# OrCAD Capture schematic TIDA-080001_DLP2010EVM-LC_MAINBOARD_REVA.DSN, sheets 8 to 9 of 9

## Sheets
8 P07: Power Supplies: size D
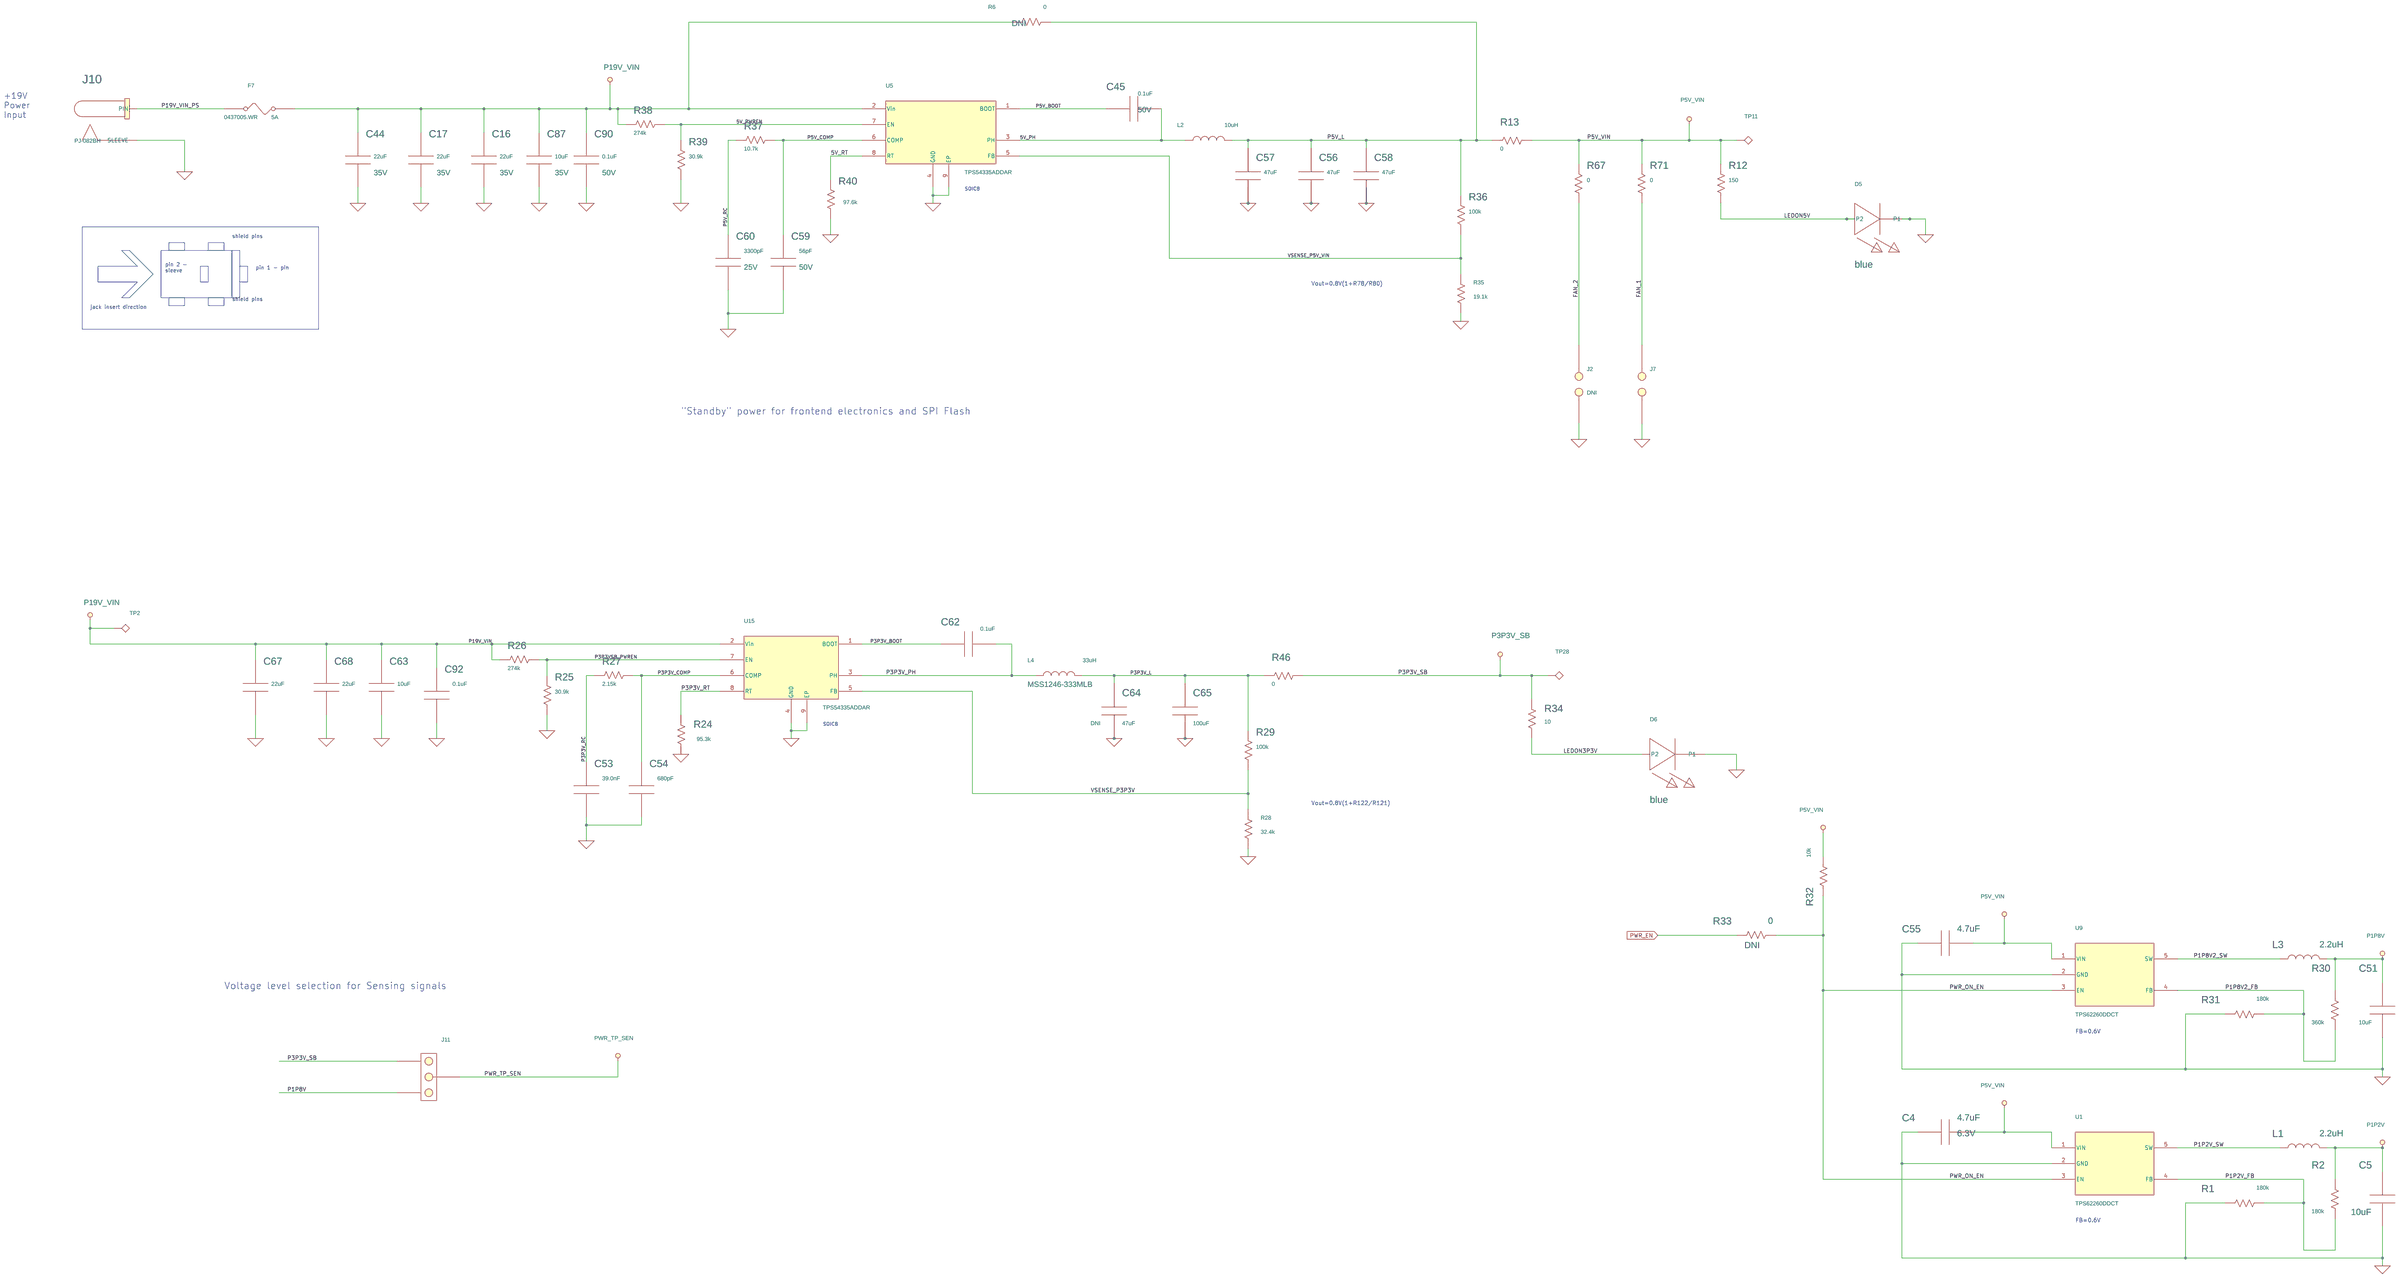
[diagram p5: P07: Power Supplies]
9 P04: MSP430, Switches, Video CN: size D

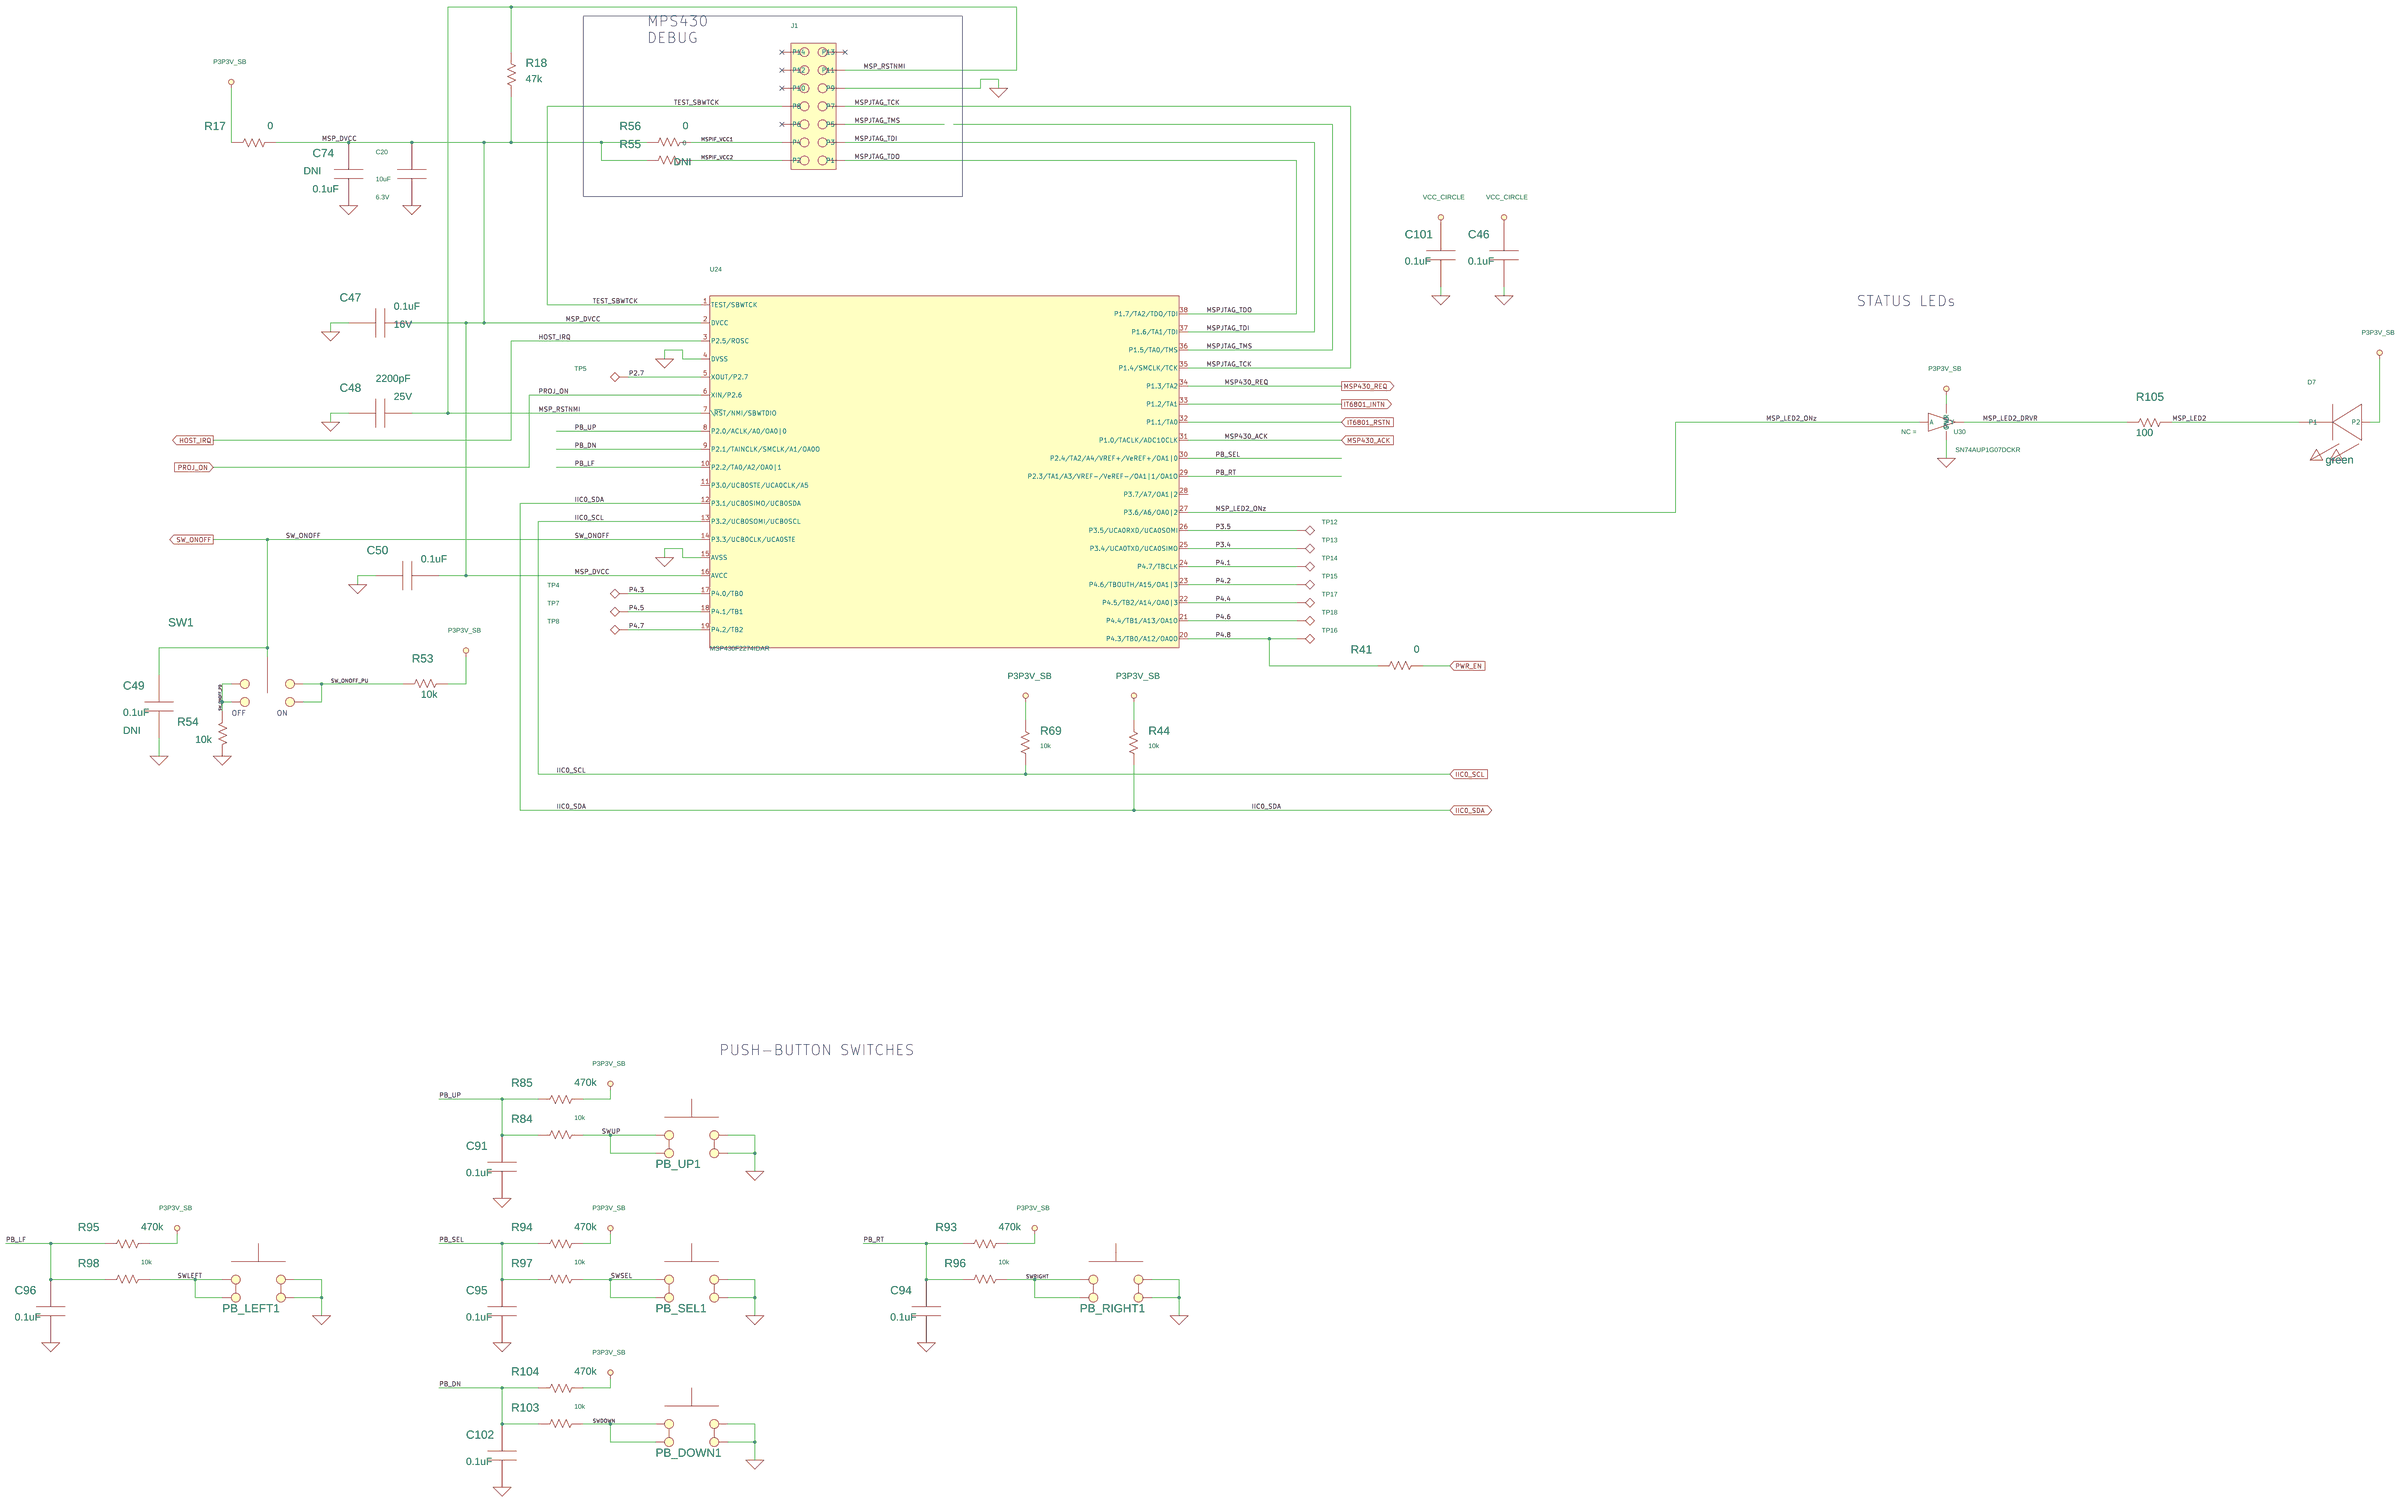
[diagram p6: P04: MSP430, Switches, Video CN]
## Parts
sheet P04: MSP430, Switches, Video CN
C20  10uF  [0603]
C46  0.1uF  [0402_AVXA]
C47  0.1uF  [0402_AVXA]
C48  2200pF  [0402]
C49  0.1uF  [0402_AVXA]
C50  0.1uF  [0402_AVXA]
C74  0.1uF  [0402_AVXA]
C91  0.1uF  [0402_AVXA]
C94  0.1uF  [0402_AVXA]
C95  0.1uF  [0402_AVXA]
C96  0.1uF  [0402_AVXA]
C101  0.1uF  [0402_AVXA]
C102  0.1uF  [0402_AVXA]
D7  green  [1206]
J1  HDR,14P,2R  [HDR14P_2R_100mil]
PB_DOWN1  KT11B1SM  [KT11B1SM]
PB_LEFT1  KT11B1SM  [KT11B1SM]
PB_RIGHT1  KT11B1SM  [KT11B1SM]
PB_SEL1  KT11B1SM  [KT11B1SM]
PB_UP1  KT11B1SM  [KT11B1SM]
R17  0  [0402]
R18  47k  [0402]
R41  0  [0402]
R44  10k  [0402]
R53  10k  [0402]
R54  10k  [0402]
R55  0  [0402]
R56  0  [0402]
R69  10k  [0402]
R84  10k  [0402]
R85  470k  [0402]
R93  470k  [0402]
R94  470k  [0402]
R95  470k  [0402]
R96  10k  [0402]
R97  10k  [0402]
R98  10k  [0402]
R103  10k  [0402]
R104  470k  [0402]
R105  100  [0402]
SW1  GT11MSCBE  [GT11MSCBE]
TP4  TP,40mil Drill,60mil Pad  [HOLE_PLATED_40mil_DRILL_60mil_PAD]
TP5  TP,40mil Drill,60mil Pad  [HOLE_PLATED_40mil_DRILL_60mil_PAD]
TP7  TP,40mil Drill,60mil Pad  [HOLE_PLATED_40mil_DRILL_60mil_PAD]
TP8  TP,40mil Drill,60mil Pad  [HOLE_PLATED_40mil_DRILL_60mil_PAD]
TP12  TP,40mil Drill,60mil Pad  [HOLE_PLATED_40mil_DRILL_60mil_PAD]
TP13  TP,40mil Drill,60mil Pad  [HOLE_PLATED_40mil_DRILL_60mil_PAD]
TP14  TP,40mil Drill,60mil Pad  [HOLE_PLATED_40mil_DRILL_60mil_PAD]
TP15  TP,40mil Drill,60mil Pad  [HOLE_PLATED_40mil_DRILL_60mil_PAD]
TP16  TP,40mil Drill,60mil Pad  [HOLE_PLATED_40mil_DRILL_60mil_PAD]
TP17  TP,40mil Drill,60mil Pad  [HOLE_PLATED_40mil_DRILL_60mil_PAD]
TP18  TP,40mil Drill,60mil Pad  [HOLE_PLATED_40mil_DRILL_60mil_PAD]
U24  MSP430F2274IDAR  [TSSOP_38_DA_R-PDSO-G]
U30  SN74AUP1G07DCK  [U_5_DCK]
sheet P07: Power Supplies
C4  4.7uF  [0402]
C5  10uF  [0603]
C16  22uF  [1206]
C17  22uF  [1206]
C44  22uF  [1206]
C45  0.1uF  [0402]
C51  10uF  [0603]
C53  39.0nF  [0402]
C54  680pF  [0402]
C55  4.7uF  [0402]
C56  47uF  [1206]
C57  47uF  [1206]
C58  47uF  [1206]
C59  56pF  [0805]
C60  3300pF  [0805]
C62  0.1uF  [0402]
C63  10uF  [0805]
C64  47uF  [1206]
C65  100uF  [1206]
C67  22uF  [1206]
C68  22uF  [1206]
C87  10uF  [0805]
C90  0.1uF  [0402]
C92  0.1uF  [0402]
D5  blue  [1206]
D6  blue  [1206]
F7  5A  [1206]
J2  HDR,2P,1R  [22Series_2P]
J7  HDR,2P,1R  [22Series_2P]
J10  PJ-082BH  [jack2_pj-082bh_cui]
J11  EM,HDR,3P,1R,2x  [HDR3X1]
L1  2.2uH  [1008_2p5mmx2mm]
L2  10uH  [IND2_XAL8080_COILCRAFT]
L3  2.2uH  [1008_2p5mmx2mm]
L4  33uH  [IND2-MSS1246_COIL]
R1  180k  [0402]
R2  180k  [0402]
R6  0  [1206]
R12  150  [0402]
R13  0  [0402]
R24  95.3k  [0402]
R25  30.9k  [0402]
R26  274k  [0402]
R27  2.15k  [0402]
R28  32.4k  [0402]
R29  100k  [0402]
R30  360k  [0402]
R31  180k  [0402]
R32  10k  [0402]
R33  0  [0402]
R34  10  [0402]
R35  19.1k  [0805]
R36  100k  [0402]
R37  10.7k  [0402]
R38  274k  [0402]
R39  30.9k  [0402]
R40  97.6k  [0402]
R46  0  [0402]
R67  0  [0402]
R71  0  [0402]
TP2  TP,12mil Drill,32mil Pad  [tp-30rd12]
TP11  TP,12mil Drill,32mil Pad  [tp-30rd12]
TP28  TP,12mil Drill,32mil Pad  [tp-30rd12]
U1  TPS62260DDCT  [TSOT-23_DDC_R-PDSO-G5]
U5  TPS54335ADDAR  [8-SO-PWRPAD_DDA_R-PDSO-G8]
U9  TPS62260DDCT  [TSOT-23_DDC_R-PDSO-G5]
U15  TPS54335ADDAR  [HSOIC8_DDA_R-PDSO-G8]

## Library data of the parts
C20 = PAS,CAP,NP,large: DigiKey: 445-4112-1-ND; DigiReel: 445-4112-6-ND; Family: passive; Index PN: 906; Lead Style: SMT; MFG: TDK; Material: x5r; P/D_NUM: C1608X5R0J106M080AB; Part Number: C1608X5R0J106M080AB; Part Specific: CAP CERAMIC 10UF 6.3V X5R 0603; Tolerance: 20%; Type: capacitor; VENDOR: TDK; VPC: 6.3V
C46 C47 C50 C91 C94-C96 C101 C102 = PAS,CAP,NP,large: DigiKey: 445-4952-1-ND; DigiReel: 445-4952-6-ND; Family: passive; Index PN: 681; Lead Style: SMT; MFG: TDK; Material: x7r; P/D_NUM: C1005X7R1C104K050BC; Part Number: C1005X7R1C104K050BC; Part Specific: CAP CER .1UF 16V X7R 0402; TOLERANCE: 10%; Type: capacitor; VENDOR: TDK; VPC: 16V
C48 = PAS,CAP,NP,large: DigiKey: 490-5419-1-ND; DigiReel: 490-5419-6-ND; Family: passive; Index PN: 1047; Lead Style: SMT; MFG: Murata; P/D_NUM: GRM155R71E222KA01D; Part Number: GRM155R71E222KA01D; Part Specific: CAP CER 2200PF 25V X7R 0402; TOLERANCE: 10%; Type: capacitor; VENDOR: Murata; VPC: 25V
C49 C74 = PAS,CAP,NP,large: DigiKey: 445-4952-1-ND; DigiReel: 445-4952-6-ND; Family: passive; Index PN: 681; Install: DNI; Lead Style: SMT; MFG: TDK; Material: x7r; P/D_NUM: C1005X7R1C104K050BC; Part Number: C1005X7R1C104K050BC; Part Specific: CAP CER .1UF 16V X7R 0402; TOLERANCE: 10%; Type: capacitor; VENDOR: TDK; VPC: 16V
D7 = PAS,DIODE,LED,large: DigiKey: 67-1357-1-ND; DigiReel: 67-1357-6-ND; Family: passive; Index PN: 31; Install: Y; Lead Style: SMT; MFG: Lumex; P/D_NUM: SML-LX1206GC-TR; Part Number: SML-LX1206GC-TR; Part Specific: LED 565NM WTR CLR GREEN 1206 SMD; Type: diode,led; VENDOR: Lumex
J1 = EM,HDR,14P,2R,2X,Narrow: DigiKey: SAM1052-07-ND; DigiReel: ---; Family: electro/mechanical; Index PN: 18; Install: Y; Lead Style: TH; MFG: Samtec; P/D_NUM: TSW-107-14-G-D; Part Number: TSW-107-14-G-D; Part Specific: CONN HEADER 14POS .100in DL GOLD; Pin Cnt: 14; Pin Spacing: 100x100mil; Row Cnt: 2; Type: header; VENDOR: Samtec
PB_DOWN1 PB_LEFT1 PB_RIGHT1 PB_SEL1 PB_UP1 = EM,SW,KT11BxSM34LFx: DigiKey: CKN1838CT-ND; DigiReel: CKN1838DKR-ND; Family: electro/mechanical; Index PN: 991; Lead Style: SMT; MFG: C&K; Part Number: KT11B1SM34LFS; Part Specific: SWITCH TACT 0.64MM SILV GWING; Type: switch
R17 R41 = PAS,R,large: DigiKey: P0.0JCT-ND; DigiReel: P0.0JDKR-ND; Family: passive; Index PN: 687; Lead Style: SMT; MFG: Panasonic; Material: chip; P/D_NUM: ERJ-2GE0R00X; Part Number: ERJ-2GE0R00X; Part Specific: RES 0.0 OHM 1/16W 0402 SMD; Power: 1/16W; Type: resistor; VPC: 1/16W; Vendor: Panasonic
R18 = PAS,R,large: DigiKey: P47.0KLCT-ND; DigiReel: P47.0KLDKR-ND; Family: passive; Index PN: 1030; Lead Style: SMT; MFG: Panasonic; Material: chip; P/D_NUM: ERJ-2RKF4702X; Part Number: ERJ-2RKF4702X; Part Specific: RES 47.0K OHM 1/10W 1% 0402 SMD; Type: resistor; VPC: 1/16W; Vendor: Panasonic
R32 R44 R69 R84 R96-R98 R103 = PAS,R,large: DigiKey: P10.0KLCT-ND; DigiReel: P10.0KLDKR-ND; Family: passive; Index PN: 680; Lead Style: SMT; MFG: Panasonic; Material: chip; P/D_NUM: ERJ-2RKF1002X; Part Number: ERJ-2RKF1002X; Part Specific: RES SMD 10K OHM 1% 1/10W 0402; Power: 1/16W; TOLERANCE: 1%; Type: resistor; VENDOR: Panasonic; VPC: 1/16W
R53 = PAS,R,large: DigiKey: P10.0KLCT-ND; DigiReel: P10.0KLDKR-ND; Family: passive; Index PN: 680; Install: Y; Lead Style: SMT; MFG: Panasonic; Material: chip; P/D_NUM: ERJ-2RKF1002X; Part Number: ERJ-2RKF1002X; Part Specific: RES SMD 10K OHM 1% 1/10W 0402; Power: 1/16W; TOLERANCE: 1%; Type: resistor; VPC: 1/16W; Vendor: Panasonic
R54 = PAS,R,large: DigiKey: P10.0KLCT-ND; DigiReel: P10.0KLDKR-ND; Family: passive; Index PN: 680; Lead Style: SMT; MFG: Panasonic; Material: chip; P/D_NUM: ERJ-2RKF1002X; Part Number: ERJ-2RKF1002X; Part Specific: RES SMD 10K OHM 1% 1/10W 0402; Power: 1/16W; TOLERANCE: 1%; Type: resistor; VPC: 1/16W; Vendor: Panasonic
R33 R55 = PAS,R,large: DigiKey: P0.0JCT-ND; DigiReel: P0.0JDKR-ND; Family: passive; Index PN: 687; Install: DNI; Lead Style: SMT; MFG: Panasonic; Material: chip; P/D_NUM: ERJ-2GE0R00X; Part Number: ERJ-2GE0R00X; Part Specific: RES 0.0 OHM 1/16W 0402 SMD; Power: 1/16W; Type: resistor; VPC: 1/16W; Vendor: Panasonic
R13 R46 R56 R67 R71 = PAS,R,large: DigiKey: P0.0JCT-ND; DigiReel: P0.0JDKR-ND; Family: passive; Index PN: 687; Install: Y; Lead Style: SMT; MFG: Panasonic; Material: chip; P/D_NUM: ERJ-2GE0R00X; Part Number: ERJ-2GE0R00X; Part Specific: RES 0.0 OHM 1/16W 0402 SMD; Power: 1/16W; Type: resistor; VPC: 1/16W; Vendor: Panasonic
R85 R93-R95 R104 = PAS,R,large: DigiKey: P470KLCT-ND; DigiReel: P470KLDKR-ND; Family: passive; Index PN: 970; Lead Style: SMT; MFG: Panasonic; Material: chip; P/D_NUM: ERJ-2RKF4703X; Part Number: ERJ-2RKF4703X; Part Specific: RES 470K OHM 1/10W 1% 0402 SMD; TOLERANCE: 1%; Type: resistor; VENDOR: Panasonic; VPC: 1/16W
R105 = PAS,R,large: DigiKey: MCS0402-100-CFCT-ND; DigiReel: MCS0402-100-CFDKR-ND; Family: passive; Lead Style: SMT; MFG: Vishay Beyschlag; Material: chip; P/D_NUM: MCS04020C1000FE000; Part Number: MCS04020C1000FE000; Part Specific: RES 100 OHM 1/10W 1% 0402 SMD; Power: 1/10W; TOLERANCE: 1%; Type: resistor; VENDOR: Vishay Beyschlag; VPC: 1/10W
SW1 = EM,SW,SPDT,GT11: DigiKey: CKN1784CT-ND; DigiReel: CKN1784DKR-ND; Family: electro/mechanical; Index PN: 1035; Install: Y; Lead Style: SMT; MFG: C&K; Part Specific: SWITCH TOGGLE SPDT ULTRAMINI SMD; Type: switch; Vendor: C&K
TP4 TP5 TP7 TP8 TP12-TP18 = BF,HOLE,PLATED,TESTPIN: DigiKey: ---; DigiReel: ---; Family: board feature; Index PN: 377; Install: DNI; Lead Style: TH; MFG: -- NOT A PART --; Type: hole,plated; Vendor: -- NOT A PART --
U24 = MSP430F2274: DigiKey: 296-21439-1-ND; DigiReel: 296-21439-6-ND; Family: processor; Index PN: 1240; Lead Style: SMT; MFG: Texas Instruments; Part Specific: IC MCU 16BIT 32KB FLASH 38TSSOP; Type: microcontroller; Vendor: Texas Instruments
U30 = LOG,BUF,OPENDRN,SN74AUP1G07DCK: DigiKey: 296-18256-1-ND; DigiReel: 296-18256-6-ND; Family: logic; Index PN: 1027; Install: Y; Lead Style: SMT; MFG: Texas Instruments; P/D_NUM: SN74AUP1G07DCKR; Part Number: SN74AUP1G07DCKR; Part Specific: IC BUFF/DVR LOW PWR N-INV SC705, open drain; Type: buffer
C4 C55 = PAS,CAP,NP,large: DigiKey: 445-7395-1-ND; DigiReel: 445-7395-6-ND; Family: passive; Index PN: 1073; Lead Style: SMT; MFG: TDK; Material: x5r; P/D_NUM: C1005X5R0J475M; Part Number: C1005X5R0J475M; Part Specific: CAP CER 4.7UF 6.3V 20% X5R 0402; TOLERANCE: 20%; Type: capacitor; VENDOR: TDK; VPC: 6.3V
C5 C51 = PAS,CAP,NP,large: DigiKey: 445-4112-1-ND; DigiReel: 445-4112-6-ND; Family: passive; Index PN: 906; Lead Style: SMT; MFG: TDK; Material: x5r; P/D_NUM: C1608X5R0J106M080AB; Part Number: C1608X5R0J106M080AB; Part Specific: CAP CERAMIC 10UF 6.3V X5R 0603; TOLERANCE: 20%; Type: capacitor; VENDOR: TDK; VPC: 6.3V
C16 C17 C44 C67 C68 = PAS,CAP,NP,large: DigiKey: 445-11739-2-ND; DigiReel: 445-11739-6-ND; Family: passive; Lead Style: SMT; MFG: Murata; P/D_NUM: C3216JB1V226M160AC; Part Number: 445-11739-2-ND; Part Specific: 22µF ±20% 35V JB 1206; TOLERANCE: 20%; Type: capacitor; VENDOR: Murata; VPC: 35V
C45 C62 C90 C92 = PAS,CAP,NP,large: DigiKey: 445-6899-1-ND; DigiReel: 445-6899-6-ND; Family: passive; Lead Style: SMT; MFG: TDK; Material: X7R; P/D_NUM: CGA2B3X7R1H104K050BB; Part Number: CGA2B3X7R1H104K050BB; Part Specific: 0.10µF 50V Ceramic Capacitor X7R 0402; TOLERANCE: 10%; Type: capacitor; VENDOR: TDK; VPC: 50V
C53 = PAS,CAP,NP,large: DigiKey: 490-8252-1-ND; DigiReel: 490-8252-6-ND; Family: passive; Lead Style: SMT; MFG: Murata; Material: X5R; P/D_NUM: GRM155R61A393KA01D; Part Number: GRM155R61A393KA01D; Part Specific: 0.039µF 10V Ceramic Capacitor X5R 0402; TOLERANCE: 10%; Type: capacitor; VENDOR: Murata; VPC: 10V
C54 = PAS,CAP,NP,large: DigiKey: 311-1030-1-ND; DigiReel: 311-1030-6-ND; Family: passive; Lead Style: SMT; MFG: Yageo; Material: X7R; P/D_NUM: CC0402KRX7R9BB681; Part Number: CC0402KRX7R9BB681; Part Specific: 680pF 50V Ceramic Capacitor X7R 0402; TOLERANCE: 10%; Type: capacitor; VENDOR: Yageo; VPC: 50V
C56-C58 = PAS,CAP,NP,large: DigiKey: 490-12439-1-ND; DigiReel: 490-12439-6-ND; Family: passive; Lead Style: SMT; MFG: Murata; P/D_NUM: GRT31CR61A476ME13L; Part Number: GRT31CR61A476ME13L; Part Specific: 47µF 10V Ceramic Capacitor X5R 1206; TOLERANCE: 20%; Type: capacitor; VENDOR: Murata; VPC: 10V
C59 = PAS,CAP,NP,large: DigiKey: 311-1108-1-ND; DigiReel: 311-1108-6-ND; Family: passive; Lead Style: SMT; MFG: Yageo; Material: NP0; P/D_NUM: CC0805JRNPO9BN560; Part Number: CC0805JRNPO9BN560; Part Specific: 56pF 50V Ceramic Capacitor C0G, NP0 0805; TOLERANCE: 5%; Type: capacitor; VENDOR: Yageo; VPC: 50V
C60 = PAS,CAP,NP,large: DigiKey: 490-12749-1-ND; DigiReel: 490-12749-6-ND; Family: passive; Lead Style: SMT; MFG: Murata; Material: X7R; P/D_NUM: GRM216R71E332KA01D; Part Number: GRM216R71E332KA01D; Part Specific: 3300pF 25V Ceramic Capacitor X7R 0805; TOLERANCE: 10%; Type: capacitor; VENDOR: Murata; VPC: 25V
C63 C87 = PAS,CAP,NP,large: DigiKey: 445-14417-1-ND; DigiReel: 445-14417-6-ND; Family: passive; Lead Style: SMT; MFG: TDK; Material: X5R; P/D_NUM: C2012X5R1V106K085AC; Part Number: C2012X5R1V106K085AC; Part Specific: 10µF 35V Ceramic Capacitor X5R 0805; TOLERANCE: 10%; Type: capacitor; VENDOR: TDK; VPC: 35V
C64 = PAS,CAP,NP,large: DigiKey: 490-12439-1-ND; DigiReel: 490-12439-6-ND; Family: passive; Install: DNI; Lead Style: SMT; MFG: Murata; P/D_NUM: GRT31CR61A476ME13L; Part Number: GRT31CR61A476ME13L; Part Specific: 47µF 10V Ceramic Capacitor X5R 1206; TOLERANCE: 20%; Type: capacitor; VENDOR: Murata; VPC: 10V
C65 = PAS,CAP,NP,large: DigiKey: 399-5620-1-ND; DigiReel: 399-5620-6-ND; Family: passive; Lead Style: SMT; MFG: KEMET; P/D_NUM: C1206C107M9PACTU; Part Number: C1206C107M9PACTU; Part Specific: 100µF 6.3V Ceramic Capacitor X5R 1206; TOLERANCE: 10%; Type: capacitor; VENDOR: KEMET; VPC: 6.3V
D5 D6 = PAS,DIODE,LED,large: DigiKey: 67-1701-1-ND; DigiReel: 67-1701-6-ND; Family: passive; Index PN: 1250; Install: Y; Lead Style: SMT; MFG: Lumex; P/D_NUM: SML-LX1206USBC-TR; Part Number: SML-LX1206USBC-TR; Part Specific: LED INGAN/SIC U-BLUE CLR 1206SMD; Type: diode,led; VENDOR: Lumex
F7 = FUSE_10A_125V_FAST_2410: FUSE BRD MNT 5A 32VAC 35VDC 1206; DigiKey: F2890CT-ND; DigiReel: F2890DKR-ND; Digikey Part Number: F2890CT-ND; Install: Y; MFG: LittleFuse; MFG Part Number: 0437005.WR; P/D_NUM: 0437005.WR; Part Number: 0437005.WR; Part Specific: FUSE BRD MNT 5A 32VAC 35VDC 1206; Type: Fuse; VPC: 35V; Vendor: LittleFuse
J2 = EM,HDR,2P,1R,2x: DigiKey: WM2700-ND; Family: electro/mechanical; Index PN: 1205; Install: DNI; Lead Style: TH; MFG: Molex; P/D_NUM: 0022112022; Part Number: 0022112022; Part Specific: CONN HEADER 2POS .100 VERT GOLD; Pin Cnt: 2; Pin Spacing: 100mil; Row Cnt: 1; Type: header; VENDOR: Molex
J7 = EM,HDR,2P,1R,2x: DigiKey: WM2700-ND; Family: electro/mechanical; Index PN: 1205; Install: Y; Lead Style: TH; MFG: Molex; P/D_NUM: 0022112022; Part Number: 0022112022; Part Specific: CONN HEADER 2POS .100 VERT GOLD; Pin Cnt: 2; Pin Spacing: 100mil; Row Cnt: 1; Type: header; VENDOR: Molex
J10 = EM,CONN,PWRJACK,PJ-082BH: DigiKey: CP-082BHCT-ND; DigiReel: CP-082BHTR-ND; Part Specific: CONN PWR JACK 2.5X5.5MM SOLDER; Type: PWR JACK; Vendor: CUI Inc
J11 = EM,HDR,3P,1R,2x_2: DigiKey: 952-2263-ND; P/D_NUM: M20-9990345; Part Number: M20-9990345; Part Specific: SIL VERTICAL PC TAIL PIN HEADER; Type: Header; Vendor: Harwin
L1 L3 = PAS,INDUCTOR,_large: DigiKey: 490-5114-1-ND; DigiReel: 490-5114-6-ND; Family: passive; Index PN: 1149; Install: Y; Lead Style: SMT; MFG: Murata; P/D_NUM: LQM2HPN2R2MG0L; Part Number: LQM2HPN2R2MG0L; Part Specific: INDUCTOR 2.2UH 20% 1300MA 1008; Type: inductor; VENDOR: Murata
L2 = PAS,INDUCTOR,_large: DigiKey: ---; DigiReel: ---; Family: passive; Lead Style: SMT; MFG: Coilcraft; P/D_NUM: XAL8080-103MEB; Part Number: 994-XAL8080-103MEB; Part Specific: Inductor 10 uH 8.7 A 20% SMD; Type: inductor; VENDOR: Coilcraft; VPC: 8.7A
L4 = PAS,INDUCTOR,_large: DigiKey: ---; DigiReel: ---; Family: passive; Lead Style: SMT; MFG: Coilcraft; P/D_NUM: MSS1246-333MLB; Part Number: MSS1246-333MLB; Part Specific: Inductor 33 uH 20 % 2.6 A; Type: inductor; VENDOR: Coilcraft; VPC: 2.6 A
R1 R2 R31 = PAS,R,large: DigiKey: 311-180KLRCT-ND; DigiReel: 311-180KLRDKR-ND; Family: passive; Index PN: 1179; Lead Style: SMT; MFG: Yageo; P/D_NUM: RC0402FR-07180KL; Part Number: RC0402FR-07180KL; Part Specific: RES 180K OHM 1/16W 1% 0402 SMD; TOLERANCE: 1%; Type: resistor; VENDOR: Yageo; VPC: 1/16W
R6 = PAS,R,large: DigiKey: 311-0.0ERCT-ND; DigiReel: 311-0.0ERTR-ND; Family: passive; Install: DNI; MFG: Yageo; Material: chip; P/D_NUM: RC1206JR-070RL; Part Number: RC1206JR-070RL; Part Specific: RES SMD 0 OHM 1/4 W 1206; Type: resistor; VPC: 1/4W; Vendor: Yageo
R12 = PAS,R,large: DigiKey: 311-150LRCT-ND; DigiReel: 311-150LRDKR-ND; Family: passive; Lead Style: SMT; MFG: Yageo; Material: Chip; P/D_NUM: RC0402FR-07150RL; Part Number: RC0402FR-07150RL; Part Specific: RES SMD 150 OHM 1% 1/16W 0402; Type: resistor; VENDOR: Yageo; VPC: 1/16W
R24 = PAS,R,large: DigiKey: 541-95.3KLCT-ND; DigiReel: 541-95.3KLDKR-ND; Family: passive; MFG: Vishay Dale; Material: chip; P/D_NUM: CRCW040295K3FKED; Part Number: CRCW040295K3FKED; Part Specific: RES SMD 95.3K OHM 1% 1/16W 0402; Power: 1/16W; TOLERANCE: 1%; Type: resistor; VENDOR: Vishay Dale; VPC: 1/16W
R25 R39 = PAS,R,large: DigiKey: 541-30.9KLCT-ND; Family: passive; MFG: Vishay Dale; Material: chip; P/D_NUM: CRCW040230K9FKED; Part Number: CRCW040230K9FKED; Part Specific: RES SMD 30.9K OHM 1% 1/16W 0402; Power: 1/16W; TOLERANCE: 1%; Type: resistor; VENDOR: Vishay Dale; VPC: 1/16W
R26 R38 = PAS,R,large: DigiKey: 541-274KLCT-ND; DigiReel: 541-274KLDKR-ND; Family: passive; MFG: Vishay Dale; Material: chip; P/D_NUM: CRCW0402274KFKED; Part Number: CRCW0402274KFKED; Part Specific: RES SMD 274K OHM 1% 1/16W 0402; Power: 1/16W; TOLERANCE: 1%; Type: resistor; VENDOR: Vishay Dale; VPC: 1/16W
R27 = PAS,R,large: DigiKey: 541-2.15KLCT-ND; DigiReel: 541-2.15KLDKR-ND; Family: passive; MFG: Vishay Dale; Material: chip; P/D_NUM: CRCW04022K15FKED; Part Number: CRCW04022K15FKED; Part Specific: RES SMD 2.15K OHM 1% 1/16W 0402; Power: 1/16W; TOLERANCE: 1%; Type: resistor; VENDOR: Vishay Dale; VPC: 1/16W
R28 = PAS,R,large: DigiKey: P32.4KLCT-ND; DigiReel: P32.4KLDKR-ND; Family: passive; MFG: Panasonic; Material: chip; P/D_NUM: ERJ-2RKF3242X; Part Number: ERJ-2RKF3242X; Part Specific: RES SMD 32.4K OHM 1% 1/10W 0402; Power: 1/10W; TOLERANCE: 1%; Type: resistor; VENDOR: Panasonic; VPC: 1/10W
R29 R36 = PAS,R,large: DigiKey: 311-100KLRCT-ND; DigiReel: 311-100KLRDKR-ND; Family: passive; Lead Style: SMT; MFG: Yageo; P/D_NUM: RC0402FR-07100KL; Part Number: RC0402FR-07100KL; Part Specific: RES SMD 100K OHM 1% 1/16W 0402; Power: 1/16W; TOLERANCE: 1%; Type: Resistor; VENDOR: Yageo; VPC: 1/16W
R30 = PAS,R,large: DigiKey: 311-360KLRCT-ND; DigiReel: 311-360KLRDKR-ND; Family: passive; Index PN: 1180; Lead Style: SMT; MFG: Yageo; P/D_NUM: RC0402FR-07360KL; Part Number: RC0402FR-07360KL; Part Specific: RES 360K OHM 1/16W 1% 0402 SMD; TOLERANCE: 1%; Type: resistor; VENDOR: Yageo; VPC: 1/16W
R34 = PAS,R,large: DigiKey: P10.0LCT-ND; DigiReel: P10.0LDKR-ND; Family: passive; Index PN: 1099; Lead Style: SMT; MFG: Panasonic; Material: chip; P/D_NUM: ERJ-2RKF10R0X; Part Number: ERJ-2RKF10R0X; Part Specific: RES 10.0 OHM 1/10W 1% 0402 SMD; TOLERANCE: 1%; Type: resistor; VENDOR: Panasonic; VPC: 1/10W
R35 = PAS,R,large: DigiKey: P19.1KCCT-ND; DigiReel: P19.1KCDKR-ND; Family: passive; MFG: Panasonic; Material: chip; P/D_NUM: ERJ-6ENF1912V; Part Number: ERJ-6ENF1912V; Part Specific: RES SMD 19.1K OHM 1% 1/8W 0805; Power: 1/8W; TOLERANCE: 1%; Type: resistor; VENDOR: Panasonic; VPC: 1/8W
R37 = PAS,R,large: DigiKey: 541-10.7KLCT-ND; Family: passive; MFG: Vishay Dale; Material: chip; P/D_NUM: CRCW040210K7FKED; Part Number: CRCW040210K7FKED; Part Specific: RES SMD 10.7K OHM 1% 1/16W 0402; Power: 1/16W; TOLERANCE: 1%; Type: resistor; VENDOR: Vishay Dale; VPC: 1/16W
R40 = PAS,R,large: DigiKey: 541-97.6KLCT-ND; Family: passive; MFG: Vishay Dale; Material: chip; P/D_NUM: CRCW040297K6FKED; Part Number: CRCW040297K6FKED; Part Specific: RES SMD 97.6K OHM 1% 1/16W 0402; Power: 1/16W; TOLERANCE: 1%; Type: resistor; VENDOR: Vishay Dale; VPC: 1/16W
TP2 TP11 TP28 = EM,TERM,TESTPOINT: Family: board feature; Index PN: 122; Install: DNI; MFG: -- NOT A PART --; Type: hole,plated; Vendor: -- NOT A PART --
U1 U9 = PWR,REG,TPS62260,TSOT23_DDC: DigiKey: 296-22469-1-ND; DigiReel: 296-22469-6-ND; Family: power; Index PN: 1147; Install: Y; Lead Style: SMT; MFG: Texas Instruments; Part Specific: IC REG BUCK SYNC ADJ TSOT23-5; Type: regulator; Vendor: Texas Instruments
U5 = RT8272_SOP8_1: DigiKey: 296-43617-1-ND; DigiReel: 296-43617-6-ND; Family: power; Index PN: 1342; Install: Y; Lead Style: SMT; MFG: Texas Instruments; Part Specific: IC REG BCK ADJ 3A SYNC 8SOPWRPAD; Type: reg,switching; Vendor: Texas Instruments
U15 = RT8272_SOP8_2: DigiKey: 296-43617-1-ND; DigiReel: 296-43617-6-ND; Family: power; Index PN: 1342; Install: Y; Lead Style: SMT; MFG: Texas Instruments; Part Specific: IC REG BCK ADJ 3A SYNC 8SOPWRPAD; Type: reg,switching; Vendor: Texas Instruments

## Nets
5V_PH: C45.2(N) L2.2 U5.3(PH)
5V_PWREN: R38.2(N2) R39.1(N1) U5.7(EN)
5V_RT: R40.1(N1) U5.8(RT)
DGND: C4.1(P) C5.2(N) C16.2(N) C17.2(N) C20.2(N) C44.2(N) C46.2(N) C47.2(N) C48.2(N) C49.2(N) C50.2(N) C51.2(N) C53.1(P) C54.1(P) C55.1(P) C56.2(N) C57.2(N) C58.2(N) C59.1(P) C60.1(P) C63.1(P) C64.2(N) C65.2(N) C67.2(N) C68.2(N) C74.2(N) C87.1(P) C90.1(P) C91.2(N) C92.1(P) C94.2(N) C95.2(N) C96.2(N) C101.2(N) C102.2(N) D5.1(P1) D6.1(P1) J1.9(P9) J2.2 J7.2 J10.2(SLEEVE) PB_DOWN1.2 PB_DOWN1.4 PB_LEFT1.2 PB_LEFT1.4 PB_RIGHT1.2 PB_RIGHT1.4 PB_SEL1.2 PB_SEL1.4 PB_UP1.2 PB_UP1.4 R1.2(N2) R24.2(N2) R25.2(N2) R28.2(N2) R31.2(N2) R35.2(N2) R39.2(N2) R40.2(N2) R54.1(N1) U1.2(GND) U5.4(GND) U5.9(EP) U9.2(GND) U15.4(GND) U15.9(EP) U24.4(DVSS) U24.15(AVSS) U30.3(GND) ; also on sheet 2 5 6 7
P5V_BOOT: C45.1(P) U5.1(BOOT)
P5V_COMP: C59.2(N) R37.2(N2) U5.6(COMP)
P5V_L: C56.1(P) C57.1(P) C58.1(P) L2.1 R6.2(N2) R13.2(N2) R36.1(N1)
P5V_RC: C60.2(N) R37.1(N1)
P5V_VIN: C4.2(N) C55.2(N) R12.1(N1) R13.1(N1) R32.1(N1) R67.2(N2) R71.2(N2) TP11.1(P1) U1.1(VIN) U9.1(VIN) ; also on sheet 2 5 6 7
P19V_VIN: C16.1(P) C17.1(P) C44.1(P) C63.2(N) C67.1(P) C68.1(P) C87.2(N) C90.2(N) C92.2(N) F7.2 R6.1(N1) R26.1(N1) R38.1(N1) TP2.1(P1) U5.2(Vin) U15.2(Vin)
P19V_VIN_PS: F7.1 J10.1(PIN)
FAN_1: J7.1 R71.1(N1)
FAN_2: J2.1 R67.1(N1)
HOST_IRQ: U24.3(P2.5/ROSC) ; also on sheet 5 7
IIC0_SCL: R69.1(N1) U24.13(P3.2/UCB0SOMI/UCB0SCL) ; also on sheet 2 5 6 7
IIC0_SDA: R44.1(N1) U24.12(P3.1/UCB0SIMO/UCB0SDA) ; also on sheet 2 5 6 7
IT6801_INTN: U24.33(P1.2/TA1) ; also on sheet 2
IT6801_RSTN: U24.32(P1.1/TA0) ; also on sheet 6
LEDON3P3V: D6.2(P2) R34.2(N2)
LEDON5V: D5.2(P2) R12.2(N2)
MSP430_ACK: U24.31(P1.0/TACLK/ADC10CLK) ; also on sheet 7
MSP430_REQ: U24.34(P1.3/TA2) ; also on sheet 7
MSP_DVCC: C20.1(P) C47.1(P) C50.1(P) C74.1(P) R17.1(N1) R18.2(N2) R55.1(N1) R56.1(N1) U24.2(DVCC) U24.16(AVCC)
MSP_LED2: D7.1(P1) R105.1(N1)
MSP_LED2_DRVR: R105.2(N2) U30.4(Y)
MSP_LED2_ONz: U24.27(P3.6/A6/OA0|2) U30.2(A)
MSP_RSTNMI: C48.1(P) J1.11(P11) R18.1(N1) U24.7(\~{RS}T/NMI/SBWTDIO)
MSPIF_VCC1: J1.4(P4) R56.2(N2)
MSPIF_VCC2: J1.2(P2) R55.2(N2)
MSPJTAG_TCK: J1.7(P7) U24.35(P1.4/SMCLK/TCK)
MSPJTAG_TDI: J1.3(P3) U24.37(P1.6/TA1/TDI)
MSPJTAG_TDO: J1.1(P1) U24.38(P1.7/TA2/TDO/TDI)
MSPJTAG_TMS: J1.5(P5) U24.36(P1.5/TA0/TMS)
P1P2V: C5.1(P) L1.2 R2.2(N2) ; also on sheet 2
P1P2V_FB: R1.1(N1) R2.1(N1) U1.4(FB)
P1P2V_SW: L1.1 U1.5(SW)
P1P8V: C51.1(P) J11.1 L3.2 R30.2(N2) ; also on sheet 5 6
P1P8V2_FB: R30.1(N1) R31.1(N1) U9.4(FB)
P1P8V2_SW: L3.1 U9.5(SW)
P2.7: TP5.1(P1) U24.5(XOUT/P2.7)
P3.4: TP13.1(P1) U24.25(P3.4/UCA0TXD/UCA0SIMO)
P3.5: TP12.1(P1) U24.26(P3.5/UCA0RXD/UCA0SOMI)
P3P3V_BOOT: C62.1(P) U15.1(BOOT)
P3P3V_COMP: C54.2(N) R27.2(N2) U15.6(COMP)
P3P3V_L: C64.1(P) C65.1(P) L4.1 R29.1(N1) R46.2(N2)
P3P3V_PH: C62.2(N) L4.2 U15.3(PH)
P3P3V_RC: C53.2(N) R27.1(N1)
P3P3V_RT: R24.1(N1) U15.8(RT)
P3P3V_SB: C46.1(P) C101.1(P) D7.2(P2) J11.3 R17.2(N2) R34.1(N1) R44.2(N2) R46.1(N1) R53.2(N2) R69.2(N2) R85.1(N1) R93.1(N1) R94.1(N1) R95.1(N1) R104.1(N1) TP28.1(P1) U30.5(PWR) ; also on sheet 2 5 6 7
P3P3VSB_PWREN: R25.1(N1) R26.2(N2) U15.7(EN)
P4.1: TP14.1(P1) U24.24(P4.7/TBCLK)
P4.2: TP15.1(P1) U24.23(P4.6/TBOUTH/A15/OA1|3)
P4.3: TP4.1(P1) U24.17(P4.0/TB0)
P4.4: TP17.1(P1) U24.22(P4.5/TB2/A14/OA0|3)
P4.5: TP7.1(P1) U24.18(P4.1/TB1)
P4.6: TP18.1(P1) U24.21(P4.4/TB1/A13/OA1O)
P4.7: TP8.1(P1) U24.19(P4.2/TB2)
P4.8: R41.1(N1) TP16.1(P1) U24.20(P4.3/TB0/A12/OA0O)
PB_DN: C102.1(P) R103.1(N1) R104.2(N2) U24.9(P2.1/TAINCLK/SMCLK/A1/OA0O)
PB_LF: C96.1(P) R95.2(N2) R98.1(N1) U24.10(P2.2/TA0/A2/OA0|1)
PB_RT: C94.1(P) R93.2(N2) R96.1(N1) U24.29(P2.3/TA1/A3/VREF-/VeREF-/OA1|1/OA1O)
PB_SEL: C95.1(P) R94.2(N2) R97.1(N1) U24.30(P2.4/TA2/A4/VREF+/VeREF+/OA1|0)
PB_UP: C91.1(P) R84.1(N1) R85.2(N2) U24.8(P2.0/ACLK/A0/OA0|0)
PROJ_ON: U24.6(XIN/P2.6) ; also on sheet 5
PWR_EN: R33.1(N1) R41.2(N2)
PWR_ON_EN: R32.2(N2) R33.2(N2) U1.3(EN) U9.3(EN)
PWR_TP_SEN: J11.2 ; also on sheet 5
SW_ONOFF: C49.1(P) SW1.2 U24.14(P3.3/UCB0CLK/UCA0STE) ; also on sheet 7
SW_ONOFF_PD: R54.2(N2) SW1.1 SW1.4
SW_ONOFF_PU: R53.1(N1) SW1.3 SW1.6
SWDOWN: PB_DOWN1.1 PB_DOWN1.3 R103.2(N2)
SWLEFT: PB_LEFT1.1 PB_LEFT1.3 R98.2(N2)
SWRIGHT: PB_RIGHT1.1 PB_RIGHT1.3 R96.2(N2)
SWSEL: PB_SEL1.1 PB_SEL1.3 R97.2(N2)
SWUP: PB_UP1.1 PB_UP1.3 R84.2(N2)
TEST_SBWTCK: J1.8(P8) U24.1(TEST/SBWTCK)
VSENSE_P3P3V: R28.1(N1) R29.2(N2) U15.5(FB)
VSENSE_P5V_VIN: R35.1(N1) R36.2(N2) U5.5(FB)

Not connected (* = marked no-connect by the designer): J1 6(P6)* 10(P10)* 12(P12)* 13(P13)* 14(P14)*; U24 11(P3.0/UCB0STE/UCA0CLK/A5) 28(P3.7/A7/OA1|2)

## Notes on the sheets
sheet 8
- +19V
  Power
  Input
- SOIC8
- shield pins
- pin 2 -
  sleeve
- pin 1 - pin
- Vout=0.8V(1+R78/R80)
- shield pins
- jack insert direction
- "Standby" power for frontend electronics and SPI Flash
- SOIC8
- Vout=0.8V(1+R122/R121)
- Voltage level selection for Sensing signals
- FB=0.6V
- FB=0.6V
sheet 9
- MPS430
  DEBUG
- STATUS LEDs
- OFF
- ON
- PUSH-BUTTON SWITCHES
